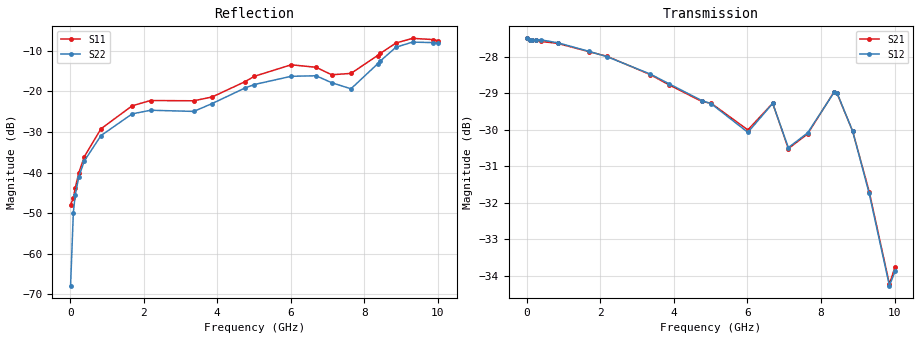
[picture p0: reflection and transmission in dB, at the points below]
! Device ID: PE43705
! Serial: 1
! Insertion: A
! Impedance: 50 ohm
! Temp: 25C
! VDD: 3.400V
! Attenuation Step: 26.50dB
#  Hz  S  RI  R  50
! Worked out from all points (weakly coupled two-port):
!   401 points, 10 MHz to 10.01 GHz, reference 50 ohm
!   highest |S21| = -27.50 dB at 10 MHz (marker M1); lowest = -34.2 dB at 9.86 GHz (marker M2)
!   lowest |S11| = -47.9 dB at 10 MHz (marker M3), VSWR 1.01, Z = 49.6 + j0.0408 ohm
!   |S11| at or under -10 dB: start of sweep to 8.523 GHz
!   |S22| runs from -67.9 to -7.8 dB; largest |S21 - S12| = 0.00073
!   S11 on the Smith chart (normalised r, x): 10 MHz: 0.99, +0.00; 4.76 GHz: 0.79, +0.12; 8.435 GHz: 0.79, +0.50; 9.31 GHz: 0.51, +0.53; 10.01 GHz: 0.46, +0.31
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1e7  -0.00401 0.000411  0.0422 -0.000165  0.0422 -0.000139  -4.19e-05 0.000402
8.5e7  -0.00377 0.00299  0.042 -0.000985  0.042 -0.000972  0.000528 0.00315
1.35e8  -0.00391 0.00509  0.042 -0.0015  0.042 -0.00149  0.00048 0.00526
2.35e8  -0.00503 0.00862  0.0419 -0.00261  0.0419 -0.00259  -0.000357 0.00889
3.85e8  -0.00806 0.0135  0.0416 -0.00399  0.0418 -0.00403  -0.00297 0.0136
8.35e8  -0.0266 0.022  0.0406 -0.00877  0.0407 -0.00873  -0.0183 0.0218
1.685e9  -0.0658 0.0086  0.037 -0.0164  0.037 -0.0165  -0.0515 0.0117
2.185e9  -0.0768 -0.00675  0.0342 -0.0205  0.0342 -0.0204  -0.0585 0.000666
3.36e9  -0.0763 -0.00561  0.0259 -0.0273  0.0259 -0.0274  -0.0564 0.00486
3.86e9  -0.0831 0.019  0.0221 -0.029  0.0223 -0.029  -0.0678 0.0201
4.76e9  -0.1108 0.0717  0.0163 -0.0305  0.0165 -0.0305  -0.0965 0.0534
5.01e9  -0.1265 0.0865  0.0151 -0.0309  0.015 -0.0309  -0.1056 0.0598
6.01e9  -0.1819 0.1094  0.00869 -0.0304  0.00885 -0.0301  -0.1328 0.0763
6.685e9  -0.173 0.096  0.0058 -0.0339  0.00571 -0.0339  -0.1383 0.0712
7.11e9  -0.1386 0.0801  0.000619 -0.0298  0.000414 -0.0299  -0.1051 0.0727
7.635e9  -0.091 0.1391  0.00108 -0.0312  0.00111 -0.0313  -0.0549 0.0924
8.36e9  -0.0332 0.274  -0.00833 -0.0347  -0.00806 -0.0347  -0.0334 0.2153
8.435e9  -0.0354 0.2914  -0.0101 -0.034  -0.00965 -0.0342  -0.036 0.234
8.86e9  -0.0872 0.3841  -0.0146 -0.0279  -0.0144 -0.028  -0.0935 0.3369
9.31e9  -0.1754 0.4135  -0.0145 -0.0216  -0.0144 -0.0215  -0.1862 0.3586
9.86e9  -0.2919 0.322  -0.00656 -0.0183  -0.00656 -0.0182  -0.3137 0.2454
1.001e10  -0.3161 0.2759  -0.00408 -0.0201  -0.00417 -0.0198  -0.3439 0.186
